VERSION 5.8 ;
BUSBITCHARS "[]" ;
DIVIDERCHAR "/" ;
UNITS
  DATABASE MICRONS 1000 ;
END UNITS
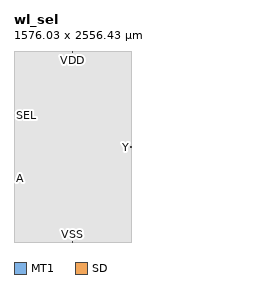
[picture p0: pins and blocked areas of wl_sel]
MACRO wl_sel
  CLASS BLOCK ;
  ORIGIN 0 0 ;
  FOREIGN wl_sel 0 0 ;
  SIZE 1576.025 BY 2556.425 ;
  SYMMETRY X Y ;
  PIN A
    DIRECTION INPUT ;
    USE SIGNAL ;
    PORT
      LAYER MT1 ;
        RECT 0 849.65 5 854.65 ;
    END
  END A
  PIN SEL
    DIRECTION INPUT ;
    USE SIGNAL ;
    PORT
      LAYER MT1 ;
        RECT 0 1701.775 5 1706.775 ;
    END
  END SEL
  PIN Y
    DIRECTION OUTPUT ;
    USE SIGNAL ;
    PORT
      LAYER MT1 ;
        RECT 1571.025 1275.7 1576.025 1280.7 ;
    END
  END Y
  PIN VDD
    DIRECTION INOUT ;
    USE POWER ;
    PORT
      LAYER SD ;
        RECT 785.5 2551.425 790.5 2556.425 ;
    END
  END VDD
  PIN VSS
    DIRECTION INOUT ;
    USE GROUND ;
    PORT
      LAYER SD ;
        RECT 785.5 0 790.5 5 ;
    END
  END VSS
  OBS
    LAYER SD ;
      RECT 0 0 1576.025 2556.425 ;
  END
END wl_sel
END LIBRARY
